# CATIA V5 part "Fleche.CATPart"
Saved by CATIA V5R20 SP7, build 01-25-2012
Part number: Fleche
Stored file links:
  D:\IFMA\COURS\2A\projet balance\Fleche.CATPart

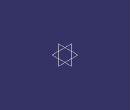
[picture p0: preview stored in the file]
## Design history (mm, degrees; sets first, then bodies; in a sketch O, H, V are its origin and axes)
Body1 (main body)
